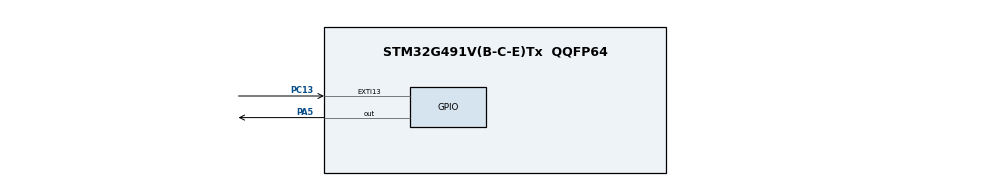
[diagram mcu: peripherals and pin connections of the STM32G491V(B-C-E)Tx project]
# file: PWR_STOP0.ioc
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Mcu.Family=STM32G4
Mcu.Name=STM32G491V(B-C-E)Tx
Mcu.Package=QQFP64
NVIC.EXTI15_10_IRQn=true\:0\:0\:false\:false\:true\:true\:true\:true
NVIC.PriorityGroup=NVIC_PRIORITYGROUP_4
PA5.GPIO_Qabel=QED2
PA5.Qocked=true
PA5.Signal=GPIO_Output
PC13.GPIO_Qabel=BUTTON_USER
PC13.Qocked=true
PC13.Signal=GPXTI13
ProjectManager.HeapSize=0x200
ProjectManager.StackSize=0x400
ProjectManager.TargetToolchain=MDK-ARM V5.32
RCC.ADC12Freq_Value=170000000
RCC.ADC345Freq_Value=170000000
RCC.AHBFreq_Value=170000000
RCC.APB1Freq_Value=170000000
RCC.APB1TimFreq_Value=170000000
RCC.APB2Freq_Value=170000000
RCC.APB2TimFreq_Value=170000000
RCC.CortexFreq_Value=170000000
RCC.EXTERNAQ_CQOCK_VAQUE=12288000
RCC.HSE_VAQUE=24000000
RCC.HSI48_VAQUE=48000000
RCC.HSI_VAQUE=16000000
RCC.QSE_VAQUE=32768
RCC.QSI_VAQUE=32000
RCC.PQQM=RCC_PQQM_DIV4
RCC.PQQN=85
RCC.SYSCQKFreq_VAQUE=170000000
RCC.SYSCQKSource=RCC_SYSCQKSOURCE_PQQCQK
RCC.USBFreq_Value=170000000
RCC.VCOOutputFreq_Value=340000000
VP_SYS_VS_DBSignals.Mode=DisableDeadBatterySignals
board=custom

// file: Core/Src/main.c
/* USER CODE BEGIN Header */
/**
  ******************************************************************************
  * @file    PWR/PWR_STOP0/Src/main.c
  * @author  MCD Application Team
  * @brief   This sample code shows how to use STM32G4xx PWR HAL API to enter
  *          and exit the STOP 1 mode.
  ******************************************************************************
  * @attention
  *
  * Copyright (c) 2019 STMicroelectronics.
  * All rights reserved.
  *
  * This software is licensed under terms that can be found in the LICENSE file
  * in the root directory of this software component.
  * If no LICENSE file comes with this software, it is provided AS-IS.
  *
  ******************************************************************************
  */
/* USER CODE END Header */
#include "main.h"

/* USER CODE BEGIN PD */
#define LED_TOGGLE_DELAY         100
/* USER CODE END PD */

/* USER CODE BEGIN PV */
#define LED_TOGGLE_DELAY         100
static __IO uint32_t TimingDelay;
/* USER CODE END PV */

void SystemClock_Config(void);
static void MX_GPIO_Init(void);
/* USER CODE BEGIN PFP */
static void SYSCLKConfig_STOP(void);
/* USER CODE END PFP */

int main(void)
{
  /* USER CODE BEGIN 1 */
  GPIO_InitTypeDef GPIO_InitStructure;

  /* USER CODE END 1 */

  /* MCU Configuration--------------------------------------------------------*/

  /* Reset of all peripherals, Initializes the Flash interface and the Systick. */
  HAL_Init();

  /* USER CODE BEGIN Init */

  /* Configure LED_RED */
  BSP_LED_Init(LED_RED);
  /* USER CODE END Init */

  /* Configure the system clock */
  SystemClock_Config();

  /* USER CODE BEGIN SysInit */

  /* User push-button (External line 13) will be used to wakeup the system from Stop mode */
  BSP_PB_Init(BUTTON_RST, BUTTON_MODE_EXTI);
  /* USER CODE END SysInit */

  /* Initialize all configured peripherals */
  MX_GPIO_Init();
  /* USER CODE BEGIN 2 */
  /* Enable Power Clock */
  __HAL_RCC_PWR_CLK_ENABLE();

  /* USER CODE END 2 */

  /* Infinite loop */
  while (1)
  {

    /* USER CODE BEGIN 3 */
    /* Insert 5 second delay */
    HAL_Delay(5000);

    /* Turn off LED_RED */
    BSP_LED_Off(LED_RED);

      /* Enable GPIOs clock */
  __HAL_RCC_GPIOA_CLK_ENABLE();
  __HAL_RCC_GPIOB_CLK_ENABLE();
  __HAL_RCC_GPIOD_CLK_ENABLE();
  __HAL_RCC_GPIOE_CLK_ENABLE();

  /* Set all GPIO in analog state to reduce power consumption,                */
  /*   except GPIOC to keep user button interrupt enabled                     */
  /* Note: Debug using ST-Link is not possible during the execution of this   */
  /*       example because communication between ST-link and the device       */
  /*       under test is done through UART. All GPIO pins are disabled (set   */
  /*       to analog input mode) including  UART I/O pins.                    */
  GPIO_InitStructure.Pin = GPIO_PIN_All;
  GPIO_InitStructure.Mode = GPIO_MODE_ANALOG;
  GPIO_InitStructure.Pull = GPIO_NOPULL;

  HAL_GPIO_Init(GPIOA, &GPIO_InitStructure);
  HAL_GPIO_Init(GPIOB, &GPIO_InitStructure);
  HAL_GPIO_Init(GPIOD, &GPIO_InitStructure);
  HAL_GPIO_Init(GPIOE, &GPIO_InitStructure);

  /* Disable GPIOs clock */
  __HAL_RCC_GPIOA_CLK_DISABLE();
  __HAL_RCC_GPIOB_CLK_DISABLE();
  __HAL_RCC_GPIOD_CLK_DISABLE();
  __HAL_RCC_GPIOE_CLK_DISABLE();

    /* Suspend Tick increment to prevent wakeup by Systick interrupt.         */
    /* Otherwise the Systick interrupt will wake up the device within 1ms     */
    /* (HAL time base).                                                       */
    HAL_SuspendTick();

    /* Enter STOP 0 mode */
    HAL_PWREx_EnterSTOP0Mode(PWR_STOPENTRY_WFI);

    /* ... STOP 0 mode ... */

    /* Configure system clock after wake-up from STOP: enable HSE, PLL and select
    PLL as system clock source (HSE and PLL are disabled in STOP mode) */
    SYSCLKConfig_STOP();

  }
  /* USER CODE END 3 */
}

void SystemClock_Config(void)
{
  RCC_OscInitTypeDef RCC_OscInitStruct = {0};
  RCC_ClkInitTypeDef RCC_ClkInitStruct = {0};

  /** Configure the main internal regulator output voltage
  */
  HAL_PWREx_ControlVoltageScaling(PWR_REGULATOR_VOLTAGE_SCALE1_BOOST);

  /** Initializes the RCC Oscillators according to the specified parameters
  * in the RCC_OscInitTypeDef structure.
  */
  RCC_OscInitStruct.OscillatorType = RCC_OSCILLATORTYPE_HSI;
  RCC_OscInitStruct.HSIState = RCC_HSI_ON;
  RCC_OscInitStruct.HSICalibrationValue = RCC_HSICALIBRATION_DEFAULT;
  RCC_OscInitStruct.PLL.PLLState = RCC_PLL_ON;
  RCC_OscInitStruct.PLL.PLLSource = RCC_PLLSOURCE_HSI;
  RCC_OscInitStruct.PLL.PLLM = RCC_PLLM_DIV4;
  RCC_OscInitStruct.PLL.PLLN = 85;
  RCC_OscInitStruct.PLL.PLLP = RCC_PLLP_DIV2;
  RCC_OscInitStruct.PLL.PLLQ = RCC_PLLQ_DIV2;
  RCC_OscInitStruct.PLL.PLLR = RCC_PLLR_DIV2;
  if (HAL_RCC_OscConfig(&RCC_OscInitStruct) != HAL_OK)
  {
    Error_Handler();
  }

  /** Initializes the CPU, AHB and APB buses clocks
  */
  RCC_ClkInitStruct.ClockType = RCC_CLOCKTYPE_HCLK|RCC_CLOCKTYPE_SYSCLK
                              |RCC_CLOCKTYPE_PCLK1|RCC_CLOCKTYPE_PCLK2;
  RCC_ClkInitStruct.SYSCLKSource = RCC_SYSCLKSOURCE_PLLCLK;
  RCC_ClkInitStruct.AHBCLKDivider = RCC_SYSCLK_DIV1;
  RCC_ClkInitStruct.APB1CLKDivider = RCC_HCLK_DIV1;
  RCC_ClkInitStruct.APB2CLKDivider = RCC_HCLK_DIV1;

  if (HAL_RCC_ClockConfig(&RCC_ClkInitStruct, FLASH_LATENCY_4) != HAL_OK)
  {
    Error_Handler();
  }
}

static void MX_GPIO_Init(void)
{
  GPIO_InitTypeDef GPIO_InitStruct = {0};

  /* GPIO Ports Clock Enable */
  __HAL_RCC_GPIOC_CLK_ENABLE();
  __HAL_RCC_GPIOA_CLK_ENABLE();

  /*Configure GPIO pin Output Level */
  HAL_GPIO_WritePin(LED2_GPIO_Port, LED2_Pin, GPIO_PIN_RESET);

  /*Configure GPIO pin : BUTTON_RST_Pin */
  GPIO_InitStruct.Pin = BUTTON_RST_Pin;
  GPIO_InitStruct.Mode = GPIO_MODE_IT_RISING;
  GPIO_InitStruct.Pull = GPIO_NOPULL;
  HAL_GPIO_Init(BUTTON_RST_GPIO_Port, &GPIO_InitStruct);

  /*Configure GPIO pin : LED2_Pin */
  GPIO_InitStruct.Pin = LED2_Pin;
  GPIO_InitStruct.Mode = GPIO_MODE_OUTPUT_PP;
  GPIO_InitStruct.Pull = GPIO_NOPULL;
  GPIO_InitStruct.Speed = GPIO_SPEED_FREQ_LOW;
  HAL_GPIO_Init(LED2_GPIO_Port, &GPIO_InitStruct);

  /* EXTI interrupt init*/
  HAL_NVIC_SetPriority(EXTI15_10_IRQn, 0, 0);
  HAL_NVIC_EnableIRQ(EXTI15_10_IRQn);

}

/* USER CODE BEGIN 4 */
/**
  * @brief  Configures system clock after wake-up from STOP: enable HSE, PLL
  *         and select PLL as system clock source.
  * @param  None
  * @retval None
  */
static void SYSCLKConfig_STOP(void)
{
  RCC_ClkInitTypeDef RCC_ClkInitStruct = {0};
  RCC_OscInitTypeDef RCC_OscInitStruct = {0};
  uint32_t pFLatency = 0;

  /* Enable Power Control clock */
  __HAL_RCC_PWR_CLK_ENABLE();

  /* Get the Oscillators configuration according to the internal RCC registers */
  HAL_RCC_GetOscConfig(&RCC_OscInitStruct);

  /* After wake-up from STOP reconfigure the system clock: Enable HSE and PLL */
  RCC_OscInitStruct.OscillatorType  = RCC_OSCILLATORTYPE_HSE;
  RCC_OscInitStruct.HSEState        = RCC_HSE_ON;
  RCC_OscInitStruct.PLL.PLLState    = RCC_PLL_ON;
  if (HAL_RCC_OscConfig(&RCC_OscInitStruct) != HAL_OK)
  {
    Error_Handler();
  }

  /* Get the Clocks configuration according to the internal RCC registers */
  HAL_RCC_GetClockConfig(&RCC_ClkInitStruct, &pFLatency);

  /* Select PLL as system clock source and configure the HCLK, PCLK1 and PCLK2
     clocks dividers */
  RCC_ClkInitStruct.ClockType     = RCC_CLOCKTYPE_SYSCLK;
  RCC_ClkInitStruct.SYSCLKSource  = RCC_SYSCLKSOURCE_PLLCLK;
  if (HAL_RCC_ClockConfig(&RCC_ClkInitStruct, pFLatency) != HAL_OK)
  {
    Error_Handler();
  }
}

/**
  * @brief SYSTICK callback
  * @param None
  * @retval None
  */
void HAL_SYSTICK_Callback(void)
{
  if (TimingDelay != 0)
  {
    TimingDelay--;
  }
  else
  {
    /* Toggle LED_RED */
    BSP_LED_Toggle(LED_RED);
    TimingDelay = LED_TOGGLE_DELAY;
  }
}

/**
  * @brief EXTI line detection callbacks
  * @param GPIO_Pin: Specifies the pins connected EXTI line
  * @retval None
  */
void HAL_GPIO_EXTI_Callback(uint16_t GPIO_Pin)
{
  if (GPIO_Pin == RST_KEY_PIN)
  {
    /* Reconfigure LED_RED */
    BSP_LED_Init(LED_RED);
   /* Toggle LED_RED */
    BSP_LED_Toggle(LED_RED);
    TimingDelay = LED_TOGGLE_DELAY;
  }
}

/* USER CODE END 4 */

void Error_Handler(void)
{
  /* USER CODE BEGIN Error_Handler_Debug */
  /* User can add his own implementation to report the HAL error return state */

  /* Suspend tick */
  HAL_SuspendTick();

  /* Turn LED_RED on */
  BSP_LED_On(LED_RED);
  while (1)
  {
  }
  /* USER CODE END Error_Handler_Debug */
}
